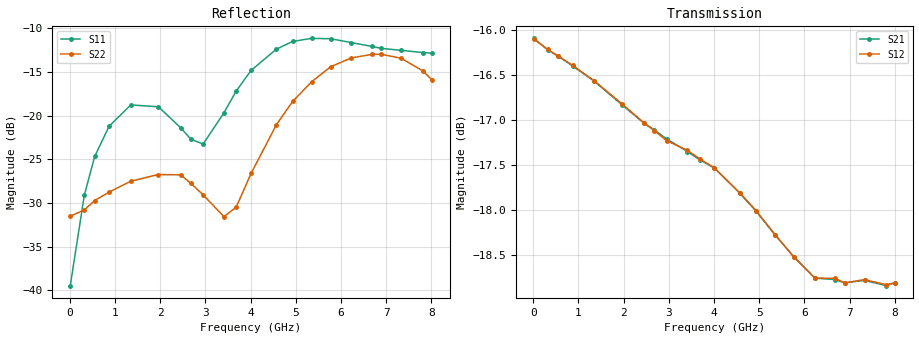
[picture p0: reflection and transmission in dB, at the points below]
!Agilent Technologies,E5071B,MY42404982,A.09.10
!Date: Mon Oct 20 18:09:45 2025
!Data & Calibration Information:
!Freq	S11:SOLT2(ON)	S21:SOLT2(ON)	S12:SOLT2(ON)	S22:SOLT2(ON)
# Hz S RI R 50
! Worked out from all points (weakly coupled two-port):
!   801 points, 10 MHz to 8.01 GHz, reference 50 ohm
!   highest |S21| = -16.09 dB at 10 MHz (marker M1); lowest = -18.8 dB at 7.81 GHz (marker M2)
!   lowest |S11| = -39.5 dB at 10 MHz (marker M3), VSWR 1.02, Z = 49 - j0.171 ohm
!   |S11| at or under -10 dB: start of sweep to end of sweep
!   |S22| runs from -31.5 to -12.9 dB; largest |S21 - S12| = 0.0019
!   S11 on the Smith chart (normalised r, x): 10 MHz: 0.98, -0.00; 4.57 GHz: 0.62, +0.11; 5.77 GHz: 1.14, +0.60; 6.89 GHz: 1.34, -0.47; 8.01 GHz: 0.65, -0.12
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1e7  -0.0105 -0.00174  0.1568 -0.00338  0.1567 -0.00354  0.0266 -0.00086
3.2e8  -0.0218 -0.0274  0.1292 -0.0848  0.1293 -0.0848  0.0236 -0.0166
5.5e8  -0.0425 -0.0401  0.0841 -0.1282  0.084 -0.1283  0.0155 -0.0288
8.7e8  -0.0798 -0.035  0.00182 -0.1514  0.00196 -0.1515  -0.00729 -0.0358
1.35e9  -0.1129 0.0232  -0.1102 -0.0995  -0.1102 -0.0996  -0.0387 -0.0168
1.96e9  -0.0509 0.1003  -0.136 0.0476  -0.1362 0.0476  -0.0338 0.0313
2.45e9  0.0358 0.0775  -0.0527 0.1305  -0.0528 0.1305  0.00225 0.0458
2.68e9  0.0628 0.0378  0.00187 0.1395  0.00166 0.1394  0.0188 0.0364
2.95e9  0.0656 -0.0207  0.0634 0.1225  0.0633 0.1222  0.0297 0.0189
3.41e9  -0.000587 -0.1039  0.1296 0.0403  0.1298 0.0403  0.0199 -0.0174
3.68e9  -0.07 -0.1192  0.1325 -0.022  0.1326 -0.0224  -0.00138 -0.0299
4.01e9  -0.1603 -0.0853  0.0983 -0.0894  0.0985 -0.0892  -0.0373 -0.0281
4.57e9  -0.2264 0.0806  -0.0181 -0.1274  -0.0178 -0.1275  -0.0824 0.0328
4.93e9  -0.174 0.2013  -0.0868 -0.091  -0.0864 -0.0915  -0.0744 0.0951
5.35e9  -0.0311 0.2753  -0.1215 -0.0109  -0.1215 -0.0116  -0.0134 0.1557
5.77e9  0.1339 0.241  -0.0966 0.0689  -0.0964 0.069  0.0852 0.1705
6.23e9  0.2456 0.0914  -0.0216 0.1134  -0.0201 0.1137  0.1866 0.1052
6.68e9  0.2312 -0.0932  0.0622 0.097  0.0625 0.097  0.2239 -0.0119
6.89e9  0.179 -0.164  0.0913 0.0695  0.0916 0.0691  0.2126 -0.0725
7.33e9  0.0119 -0.2363  0.1146 -0.0109  0.1147 -0.011  0.1341 -0.1658
7.81e9  -0.1664 -0.1586  0.07 -0.0904  0.0701 -0.0905  0.00404 -0.1803
8.01e9  -0.2089 -0.0911  0.0351 -0.1093  0.0356 -0.1091  -0.0417 -0.1552
